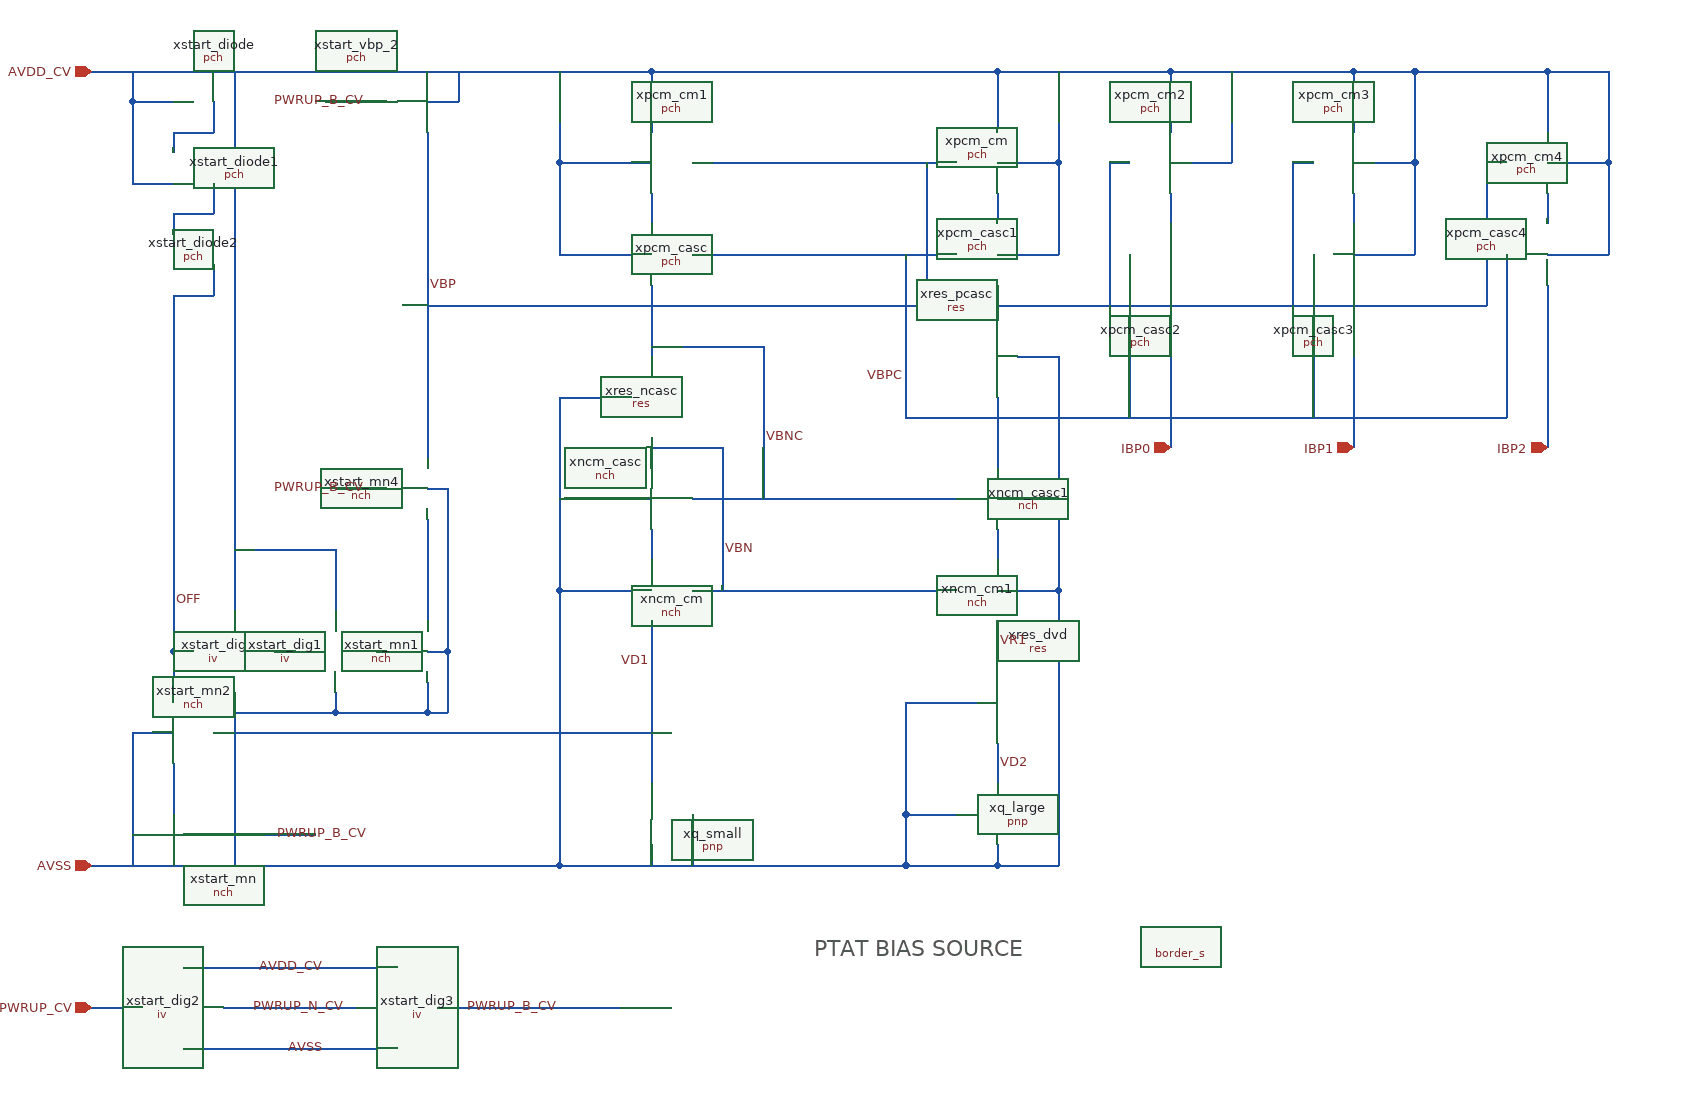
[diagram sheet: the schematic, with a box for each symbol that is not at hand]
v {xschem version=3.1.0 file_version=1.2
}
G {}
K {}
V {}
S {}
E {}
T {PTAT BIAS SOURCE} 20 70 0 0 1 1 {}
N -230 -50 -230 0 {
lab=AVSS}
N -230 0 -150 0 {
lab=AVSS}
N 110 -50 160 -50 {
lab=AVSS}
N 110 -50 110 0 {
lab=AVSS}
N 110 0 200 0 {
lab=AVSS}
N 200 -20 200 0 {
lab=AVSS}
N -150 0 110 0 {
lab=AVSS}
N 200 -110 200 -80 {
lab=VD2}
N 110 -160 180 -160 {
lab=AVSS}
N 110 -160 110 -50 {
lab=AVSS}
N 200 -120 200 -110 {
lab=VD2}
N 200 -240 200 -200 {
lab=VR1}
N -140 -240 -140 -80 {
lab=VD1}
N -230 -270 -140 -270 {
lab=AVSS}
N -230 -270 -230 -50 {
lab=AVSS}
N -100 -270 160 -270 {
lab=VBN}
N 200 -270 260 -270 {
lab=AVSS}
N 260 -270 260 0 {
lab=AVSS}
N 200 -0 260 0 {
lab=AVSS}
N -70 -410 -70 -270 {
lab=VBN}
N -230 -690 -140 -690 {
lab=AVDD_CV}
N 200 -690 260 -690 {
lab=AVDD_CV}
N -100 -690 160 -690 {
lab=VBP}
N -140 -780 -140 -720 {
lab=AVDD_CV}
N -140 -780 200 -780 {
lab=AVDD_CV}
N 200 -780 200 -720 {
lab=AVDD_CV}
N 370 -690 430 -690 {
lab=AVDD_CV}
N 200 -780 370 -780 {
lab=AVDD_CV}
N 550 -690 610 -690 {
lab=AVDD_CV}
N 370 -780 550 -780 {
lab=AVDD_CV}
N -310 -0 -230 0 {
lab=AVSS}
N -360 0 -310 0 {
lab=AVSS}
N -660 0 -360 0 {
lab=AVSS}
N -690 0 -660 0 {
lab=AVSS}
N -690 -780 -140 -780 {
lab=AVDD_CV}
N 740 -690 800 -690 {
lab=AVDD_CV}
N -230 -780 -230 -690 {
lab=AVDD_CV}
N 260 -780 260 -690 {
lab=AVDD_CV}
N 610 -780 610 -690 {
lab=AVDD_CV}
N 550 -780 610 -780 {
lab=AVDD_CV}
N 610 -780 740 -780 {
lab=AVDD_CV}
N 800 -780 800 -690 {
lab=AVDD_CV}
N 740 -780 800 -780 {
lab=AVDD_CV}
N -360 -210 -340 -210 {
lab=AVSS}
N -570 -750 -570 -720 {
lab=#net1}
N -610 -720 -570 -720 {
lab=#net1}
N -650 -750 -610 -750 {
lab=AVDD_CV}
N -610 -100 -610 -50 {
lab=#net2}
N 430 -780 430 -690 {
lab=AVDD_CV}
N -410 -210 -400 -210 {
lab=#net3}
N -510 -210 -490 -210 {
lab=#net4}
N -550 -780 -550 -250 {
lab=AVDD_CV}
N -610 -210 -590 -210 {
lab=OFF}
N -550 -170 -550 0 {
lab=AVSS}
N -450 -270 -450 -250 {
lab=AVDD_CV}
N -550 -310 -450 -310 {
lab=AVDD_CV}
N -550 -150 -450 -150 {
lab=AVSS}
N -450 -170 -450 -150 {
lab=AVSS}
N -140 -20 -140 -0 {
lab=AVSS}
N -100 -50 -100 0 {
lab=AVSS}
N -570 -130 -140 -130 {
lab=VD1}
N -360 -180 -360 -150 {
lab=AVSS}
N -450 -150 -360 -150 {
lab=AVSS}
N -340 -210 -340 -150 {
lab=AVSS}
N -360 -150 -340 -150 {
lab=AVSS}
N -650 -780 -650 -750 {
lab=AVDD_CV}
N 370 -780 370 -720 {
lab=AVDD_CV}
N 550 -780 550 -720 {
lab=AVDD_CV}
N 740 -780 740 -720 {
lab=AVDD_CV}
N -690 140 -640 140 {
lab=PWRUP_CV}
N -560 140 -430 140 {
lab=PWRUP_N_CV}
N -600 100 -390 100 {
lab=AVDD_CV}
N -600 180 -390 180 {
lab=AVSS}
N -650 -130 -610 -130 {
lab=AVSS}
N -650 -130 -650 -50 {
lab=AVSS}
N -350 140 -220 140 {
lab=PWRUP_B_CV}
N -220 140 -170 140 {
lab=PWRUP_B_CV}
N -650 -50 -650 -0 {
lab=AVSS}
N -650 -30 -610 -30 {
lab=AVSS}
N -570 -30 -470 -30 {
lab=PWRUP_B_CV}
N -360 -750 -330 -750 {
lab=AVDD_CV}
N -330 -780 -330 -750 {
lab=AVDD_CV}
N -460 -750 -400 -750 {
lab=PWRUP_B_CV}
N -360 -280 -360 -240 {
lab=#net5}
N -450 -310 -450 -270 {
lab=AVDD_CV}
N -450 -370 -400 -370 {
lab=PWRUP_B_CV}
N -360 -720 -360 -620 {
lab=VBP}
N -610 -210 -610 -160 {
lab=OFF}
N -570 -670 -570 -640 {
lab=#net6}
N -610 -640 -570 -640 {
lab=#net6}
N -570 -590 -570 -560 {
lab=OFF}
N -610 -560 -570 -560 {
lab=OFF}
N -610 -640 -610 -620 {
lab=#net6}
N -610 -720 -610 -700 {
lab=#net1}
N -650 -670 -610 -670 {
lab=AVDD_CV}
N -650 -750 -650 -670 {
lab=AVDD_CV}
N -610 -560 -610 -210 {
lab=OFF}
N -360 -620 -360 -400 {
lab=VBP}
N -360 -340 -360 -280 {
lab=#net5}
N -360 -370 -340 -370 {
lab=AVSS}
N -340 -370 -340 -210 {
lab=AVSS}
N 550 -600 610 -600 {
lab=AVDD_CV}
N 610 -690 610 -600 {
lab=AVDD_CV}
N 740 -600 800 -600 {
lab=AVDD_CV}
N 800 -690 800 -600 {
lab=AVDD_CV}
N 550 -570 550 -410 {
lab=IBP1}
N 370 -570 370 -410 {
lab=IBP0}
N 740 -570 740 -410 {
lab=IBP2}
N -140 -420 -140 -390 {
lab=VBN}
N -230 -460 -160 -460 {
lab=AVSS}
N -230 -460 -230 -270 {
lab=AVSS}
N -140 -330 -140 -300 {
lab=#net7}
N -230 -360 -140 -360 {
lab=AVSS}
N -230 -600 -140 -600 {
lab=AVDD_CV}
N -230 -690 -230 -600 {
lab=AVDD_CV}
N -140 -660 -140 -630 {
lab=#net8}
N -140 -570 -140 -500 {
lab=VBNC}
N -140 -410 -70 -410 {
lab=VBN}
N -100 -360 160 -360 {
lab=VBNC}
N -30 -510 -30 -360 {
lab=VBNC}
N -140 -510 -30 -510 {
lab=VBNC}
N 200 -460 200 -390 {
lab=VBPC}
N 220 -500 260 -500 {
lab=AVSS}
N 260 -500 260 -270 {
lab=AVSS}
N 200 -330 200 -300 {
lab=#net9}
N 200 -360 260 -360 {
lab=AVSS}
N -100 -600 160 -600 {
lab=VBPC}
N 200 -570 200 -540 {
lab=VBP}
N 200 -600 260 -600 {
lab=AVDD_CV}
N 260 -690 260 -600 {
lab=AVDD_CV}
N 200 -660 200 -630 {
lab=#net10}
N 130 -690 130 -550 {
lab=VBP}
N 130 -550 200 -550 {
lab=VBP}
N 110 -440 200 -440 {
lab=VBPC}
N 110 -600 110 -440 {
lab=VBPC}
N 200 -550 680 -550 {
lab=VBP}
N 700 -600 700 -440 {
lab=VBPC}
N 200 -440 700 -440 {
lab=VBPC}
N 330 -600 330 -440 {
lab=VBPC}
N 510 -600 510 -440 {
lab=VBPC}
N 680 -690 680 -550 {
lab=VBP}
N 680 -690 700 -690 {
lab=VBP}
N 490 -690 490 -550 {
lab=VBP}
N 490 -690 510 -690 {
lab=VBP}
N 310 -690 310 -550 {
lab=VBP}
N 310 -690 330 -690 {
lab=VBP}
N -360 -550 130 -550 {
lab=VBP}
N 370 -660 370 -630 {
lab=#net11}
N 550 -660 550 -630 {
lab=#net12}
N 740 -660 740 -630 {
lab=#net13}
C {cborder/border_s.sym} 380 80 0 0 {}
C {devices/ipin.sym} -690 140 0 0 {name=p1 lab=PWRUP_CV}
C {devices/ipin.sym} 370 -410 3 0 {name=p2 lab=IBP0}
C {devices/ipin.sym} 550 -410 3 0 {name=p3 lab=IBP1}
C {devices/ipin.sym} 740 -410 3 0 {name=p4 lab=IBP2}
C {devices/ipin.sym} -690 -780 0 0 {name=p5 lab=AVDD_CV}
C {devices/ipin.sym} -690 0 0 0 {name=p6 lab=AVSS}
C {cic/res.sym} 200 -200 1 0 {name=xres_dvd}
C {cic/pch.sym} 160 -690 0 0 {name=xpcm_cm}
C {cic/pch.sym} -100 -690 0 1 {name=xpcm_cm1}
C {cic/pch.sym} 330 -690 0 0 {name=xpcm_cm2}
C {cic/pch.sym} 510 -690 0 0 {name=xpcm_cm3}
C {cic/pch.sym} 700 -690 0 0 {name=xpcm_cm4}
C {cic/nch.sym} -100 -270 0 1 {name=xncm_cm}
C {cic/nch.sym} 160 -270 0 0 {name=xncm_cm1}
C {cic/pnp.sym} -100 -50 0 1 {name=xq_small}
C {cic/pnp.sym} 160 -50 0 0 {name=xq_large}
C {cic/nch.sym} -570 -30 0 1 {name=xstart_mn}
C {cic/nch.sym} -400 -210 0 0 {name=xstart_mn1}
C {cic/nch.sym} -400 -370 0 0 {name=xstart_mn4}
C {cic/nch.sym} -570 -130 0 1 {name=xstart_mn2}
C {cic/pch.sym} -400 -750 0 0 {name=xstart_vbp_2}
C {cic/pch.sym} -570 -750 0 1 {name=xstart_diode}
C {cic/pch.sym} -570 -670 0 1 {name=xstart_diode1}
C {cic/pch.sym} -570 -590 0 1 {name=xstart_diode2}
C {cic/iv.sym} -590 -210 0 0 {name=xstart_dig}
C {cic/iv.sym} -490 -210 0 0 {name=xstart_dig1}
C {cic/iv.sym} -640 140 0 0 {name=xstart_dig2}
C {cic/iv.sym} -430 140 0 0 {name=xstart_dig3}
C {devices/lab_pin.sym} 200 -100 0 1 {name=l2 sig_type=std_logic lab=VD2}
C {devices/lab_pin.sym} 200 -220 0 1 {name=l3 sig_type=std_logic lab=VR1}
C {devices/lab_pin.sym} -140 -200 2 1 {name=l4 sig_type=std_logic lab=VD1}
C {devices/lab_pin.sym} -610 -260 2 0 {name=l8 sig_type=std_logic lab=OFF}
C {devices/lab_pin.sym} -360 -570 2 0 {name=l10 sig_type=std_logic lab=VBP}
C {devices/lab_pin.sym} -70 -310 2 0 {name=l11 sig_type=std_logic lab=VBN}
C {devices/lab_wire.sym} -440 140 0 0 {name=p7 sig_type=std_logic lab=PWRUP_N_CV}
C {devices/lab_wire.sym} -460 100 0 0 {name=p8 sig_type=std_logic lab=AVDD_CV}
C {devices/lab_wire.sym} -460 180 0 0 {name=p9 sig_type=std_logic lab=AVSS}
C {devices/lab_wire.sym} -230 140 0 0 {name=p10 sig_type=std_logic lab=PWRUP_B_CV}
C {devices/lab_wire.sym} -420 -750 0 0 {name=p11 sig_type=std_logic lab=PWRUP_B_CV}
C {devices/lab_wire.sym} -420 -370 0 0 {name=p13 sig_type=std_logic lab=PWRUP_B_CV}
C {devices/lab_wire.sym} -510 -30 0 1 {name=p12 sig_type=std_logic lab=PWRUP_B_CV}
C {cic/nch.sym} -100 -360 0 1 {name=xncm_casc}
C {cic/nch.sym} 160 -360 0 0 {name=xncm_casc1}
C {cic/pch.sym} -100 -600 0 1 {name=xpcm_casc}
C {cic/pch.sym} 160 -600 0 0 {name=xpcm_casc1}
C {cic/pch.sym} 330 -600 0 0 {name=xpcm_casc2}
C {cic/pch.sym} 510 -600 0 0 {name=xpcm_casc3}
C {cic/pch.sym} 700 -600 0 0 {name=xpcm_casc4}
C {cic/res.sym} 200 -540 3 1 {name=xres_pcasc}
C {cic/res.sym} -140 -500 1 0 {name=xres_ncasc}
C {devices/lab_pin.sym} -30 -420 2 0 {name=l1 sig_type=std_logic lab=VBNC}
C {devices/lab_pin.sym} 110 -480 2 1 {name=l5 sig_type=std_logic lab=VBPC}
